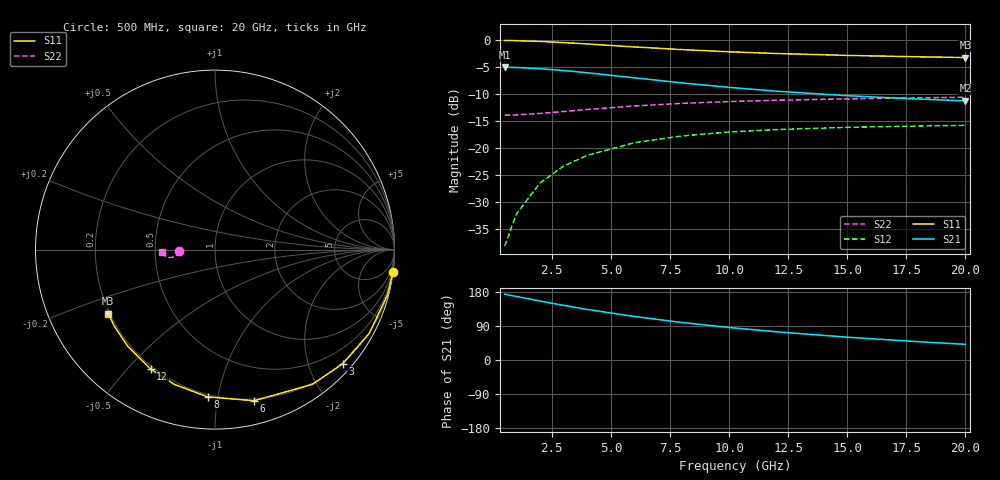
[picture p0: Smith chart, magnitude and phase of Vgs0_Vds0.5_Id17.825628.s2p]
# Hz S RI R 50
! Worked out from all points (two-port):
!   12 points, 500 MHz to 20 GHz, reference 50 ohm
!   highest |S21| = -4.97 dB at 500 MHz (marker M1); lowest = -11.2 dB at 20 GHz (marker M2)
!   |S21| within 3 dB of the highest: start of sweep to 8.236 GHz
!   lowest |S11| = -3.2 dB at 20 GHz (marker M3), VSWR 5.53, Z = 9.71 - j13.4 ohm
!   |S11| at or under -10 dB: nowhere
!   |S22| runs from -13.9 to -10.5 dB; largest |S21 - S12| = 0.56
!   S11 on the Smith chart (normalised r, x): 500 MHz: 0, -16; 3 GHz: 0.18, -2.61; 6 GHz: 0.18, -1.28; 8 GHz: 0.19, -0.93; 12 GHz: 0.19, -0.58; 20 GHz: 0.19, -0.27
5e8  0.9905 -0.1264  -0.5611 0.0612  0.000995 0.0124  -0.2023 -0.00658
1e9  0.9626 -0.2487  -0.5476 0.1204  0.00392 0.0243  -0.2038 -0.013
2e9  0.8591 -0.4672  -0.4976 0.2262  0.0148 0.0455  -0.2091 -0.0244
3e9  0.711 -0.6362  -0.4261 0.3081  0.0302 0.0615  -0.2169 -0.0333
4e9  0.5428 -0.7506  -0.3449 0.3637  0.0478 0.0717  -0.2257 -0.0394
6e9  0.2181 -0.842  -0.1881 0.4086  0.0817 0.0778  -0.243 -0.0445
8e9  -0.0403 -0.8207  -0.0632 0.3991  0.1085 0.072  -0.2573 -0.0437
1e10  -0.2269 -0.7507  0.027 0.3663  0.1277 0.0612  -0.2682 -0.0402
1.2e10  -0.3582 -0.6658  0.0907 0.3262  0.141 0.0488  -0.2766 -0.0355
1.5e10  -0.4858 -0.5393  0.1528 0.2667  0.1536 0.0303  -0.286 -0.0279
1.8e10  -0.5618 -0.4254  0.1903 0.2136  0.1605 0.0133  -0.2931 -0.02
2e10  -0.5945 -0.3575  0.2068 0.1821  0.1632 0.00284  -0.297 -0.0146
